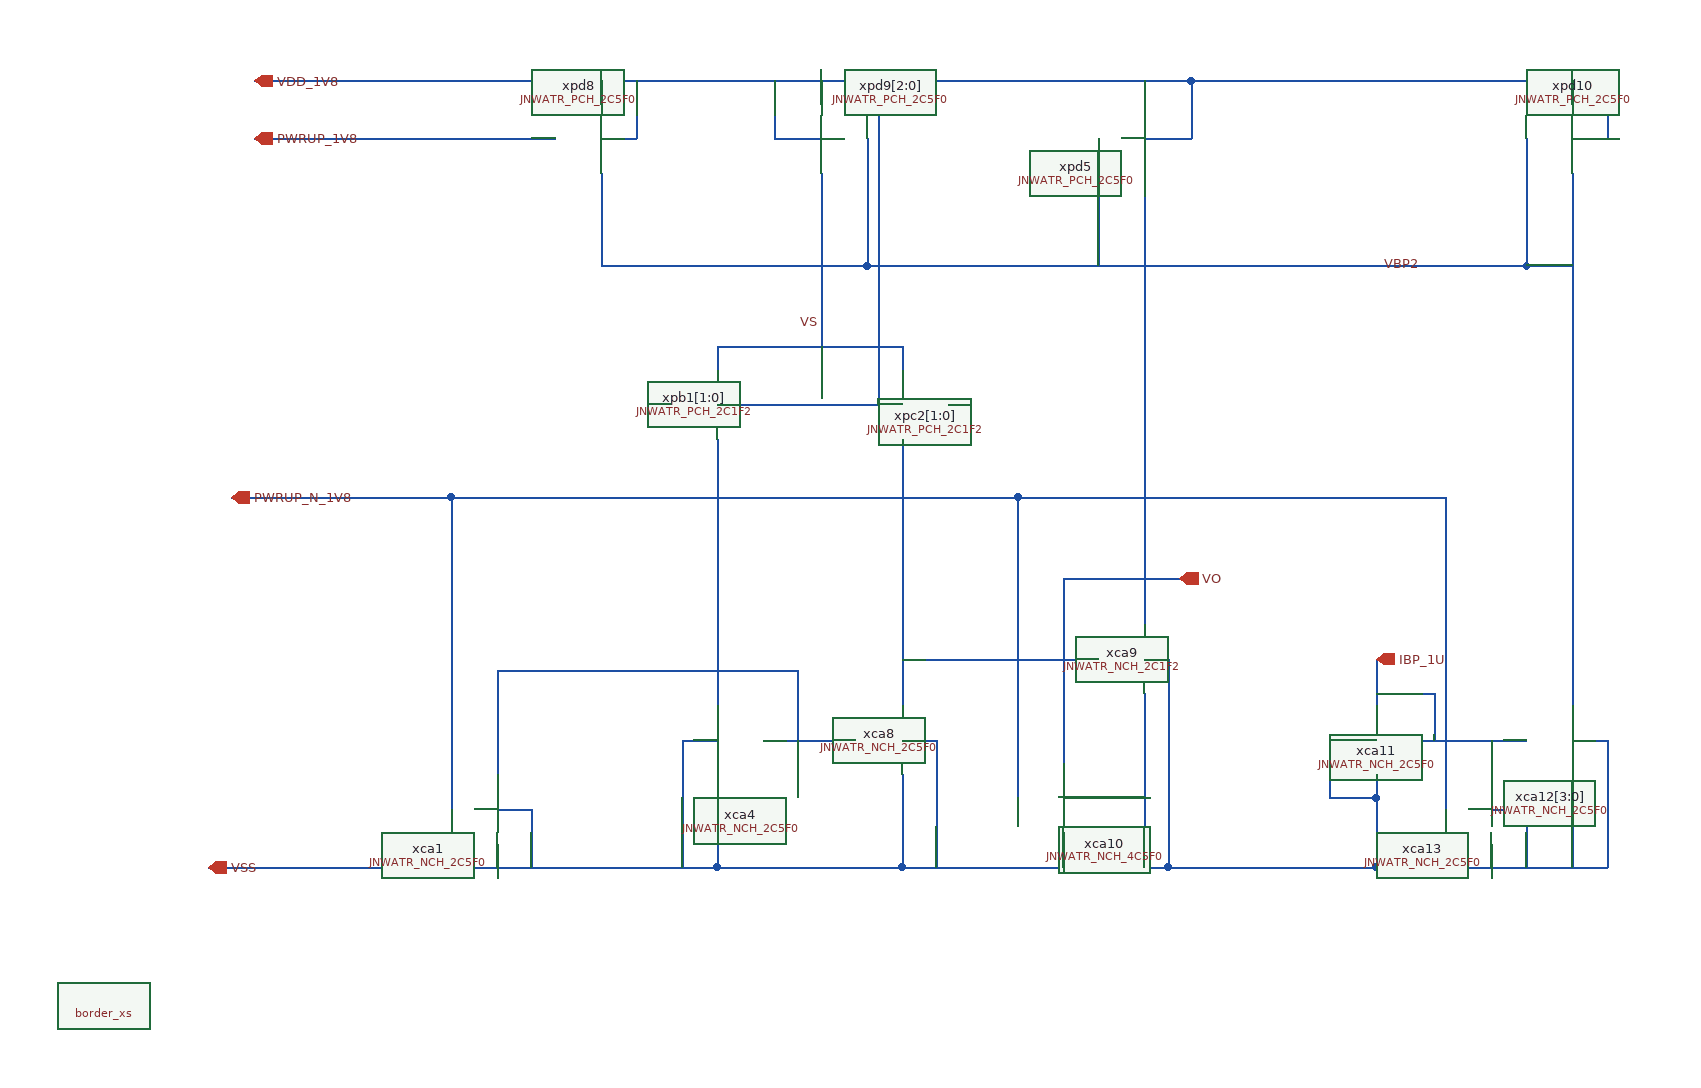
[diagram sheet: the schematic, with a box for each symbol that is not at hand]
v {xschem version=3.4.7 file_version=1.2}
G {}
K {}
V {}
S {}
E {}
N 90 -130 200 -130 {lab=VSS}
N 130 -810 190 -810 {lab=VDD_1V8}
N 190 -810 590 -810 {lab=VDD_1V8}
N 590 -810 630 -810 {lab=VDD_1V8}
N 530 -530 690 -530 {lab=VDD_1V8}
N 530 -580 530 -570 {lab=VS}
N 530 -580 600 -580 {lab=VS}
N 530 -570 530 -560 {lab=VS}
N 600 -580 690 -580 {lab=VS}
N 690 -580 690 -570 {lab=VS}
N 690 -570 690 -560 {lab=VS}
N 490 -130 530 -130 {lab=VSS}
N 530 -130 690 -130 {lab=VSS}
N 200 -130 490 -130 {lab=VSS}
N 670 -810 670 -530 {lab=VDD_1V8}
N 630 -810 670 -810 {lab=VDD_1V8}
N 860 -760 860 -710 {lab=VBP2}
N 900 -760 940 -760 {lab=VDD_1V8}
N 940 -810 940 -760 {lab=VDD_1V8}
N 670 -810 940 -810 {lab=VDD_1V8}
N 900 -810 900 -790 {lab=VDD_1V8}
N 690 -130 920 -130 {lab=VSS}
N 900 -380 930 -380 {lab=VO}
N 730 -530 750 -530 {lab=VIP}
N 470 -530 490 -530 {lab=VIN}
N 620 -590 620 -580 {lab=VS}
N 620 -600 620 -590 {lab=VS}
N 530 -210 530 -130 {lab=VSS}
N 690 -210 690 -130 {lab=VSS}
N 340 -180 370 -180 {lab=VSS}
N 370 -180 370 -130 {lab=VSS}
N 340 -150 340 -130 {lab=VSS}
N 340 -240 340 -210 {lab=#net1}
N 530 -500 530 -270 {lab=#net1}
N 690 -500 690 -270 {lab=#net2}
N 260 -760 320 -760 {lab=PWRUP_1V8}
N 130 -760 260 -760 {lab=PWRUP_1V8}
N 110 -450 290 -450 {lab=PWRUP_N_1V8}
N 290 -450 300 -450 {lab=PWRUP_N_1V8}
N 300 -450 300 -180 {lab=PWRUP_N_1V8}
N 300 -450 790 -450 {lab=PWRUP_N_1V8}
N 620 -730 620 -600 {lab=VS}
N 1100 -310 1100 -270 {lab=IBP_1U}
N 1060 -240 1100 -240 {lab=VSS}
N 1060 -240 1060 -190 {lab=VSS}
N 1060 -190 1100 -190 {lab=VSS}
N 1100 -210 1100 -190 {lab=VSS}
N 1100 -190 1100 -130 {lab=VSS}
N 920 -130 1100 -130 {lab=VSS}
N 1270 -240 1300 -240 {lab=VSS}
N 1300 -240 1300 -130 {lab=VSS}
N 1100 -130 1300 -130 {lab=VSS}
N 1270 -210 1270 -130 {lab=VSS}
N 1200 -180 1230 -180 {lab=VSS}
N 1230 -180 1230 -130 {lab=VSS}
N 1200 -150 1200 -130 {lab=VSS}
N 1140 -240 1230 -240 {lab=IBP_1U}
N 1200 -240 1200 -210 {lab=IBP_1U}
N 1270 -730 1270 -270 {lab=VBP2}
N 1270 -760 1300 -760 {lab=VDD_1V8}
N 1300 -810 1300 -760 {lab=VDD_1V8}
N 940 -810 1300 -810 {lab=VDD_1V8}
N 1270 -810 1270 -790 {lab=VDD_1V8}
N 580 -760 620 -760 {lab=VDD_1V8}
N 580 -810 580 -760 {lab=VDD_1V8}
N 620 -810 620 -790 {lab=VDD_1V8}
N 660 -760 660 -650 {lab=VBP2}
N 660 -650 1220 -650 {lab=VBP2}
N 1220 -650 1230 -650 {lab=VBP2}
N 1230 -760 1230 -650 {lab=VBP2}
N 790 -450 1160 -450 {lab=PWRUP_N_1V8}
N 1160 -450 1160 -180 {lab=PWRUP_N_1V8}
N 1230 -650 1270 -650 {lab=VBP2}
N 1100 -280 1150 -280 {lab=IBP_1U}
N 1150 -280 1150 -240 {lab=IBP_1U}
N 860 -710 860 -650 {lab=VBP2}
N 500 -240 530 -240 {lab=VSS}
N 500 -240 500 -130 {lab=VSS}
N 690 -240 720 -240 {lab=VSS}
N 720 -240 720 -130 {lab=VSS}
N 570 -240 650 -240 {lab=#net1}
N 530 -300 600 -300 {lab=#net1}
N 600 -300 600 -240 {lab=#net1}
N 340 -300 530 -300 {lab=#net1}
N 340 -300 340 -240 {lab=#net1}
N 690 -310 860 -310 {lab=#net2}
N 790 -450 790 -190 {lab=PWRUP_N_1V8}
N 830 -380 830 -220 {lab=VO}
N 830 -380 900 -380 {lab=VO}
N 900 -730 900 -340 {lab=VO}
N 900 -310 920 -310 {lab=VSS}
N 920 -310 920 -130 {lab=VSS}
N 900 -280 900 -130 {lab=VSS}
N 830 -190 900 -190 {lab=VSS}
N 830 -160 830 -130 {lab=VSS}
N 430 -760 460 -760 {lab=VDD_1V8}
N 460 -810 460 -760 {lab=VDD_1V8}
N 430 -810 430 -790 {lab=VDD_1V8}
N 430 -730 430 -650 {lab=VBP2}
N 430 -650 660 -650 {lab=VBP2}
N 320 -760 390 -760 {lab=PWRUP_1V8}
C {devices/opin.sym} 930 -380 0 0 {name=p1 lab=VO}
C {devices/ipin.sym} 750 -530 2 0 {name=p2 lab=VIP}
C {devices/ipin.sym} 470 -530 2 1 {name=p3 lab=VIN}
C {devices/ipin.sym} 130 -810 2 1 {name=p4 lab=VDD_1V8}
C {devices/ipin.sym} 90 -130 2 1 {name=p5 lab=VSS}
C {JNW_ATR_SKY130A/JNWATR_PCH_2C1F2.sym} 490 -530 0 0 {name=xpb1[1:0]}
C {JNW_ATR_SKY130A/JNWATR_PCH_2C1F2.sym} 730 -530 0 1 {name=xpc2[1:0]}
C {JNW_ATR_SKY130A/JNWATR_NCH_2C5F0.sym} 570 -240 0 1 {name=xca4}
C {JNW_ATR_SKY130A/JNWATR_NCH_2C5F0.sym} 650 -240 0 0 {name=xca8}
C {cborder/border_xs.sym} 0 -10 0 0 {user="Carsten Wulff" company="Carsten Wulff Software"}
C {JNW_ATR_SKY130A/JNWATR_PCH_2C5F0.sym} 860 -760 0 0 {name=xpd5}
C {JNW_ATR_SKY130A/JNWATR_NCH_2C1F2.sym} 860 -310 0 0 {name=xca9}
C {devices/ipin.sym} 110 -450 2 1 {name=p9 lab=PWRUP_N_1V8}
C {JNW_ATR_SKY130A/JNWATR_PCH_2C5F0.sym} 390 -760 0 0 {name=xpd8}
C {JNW_ATR_SKY130A/JNWATR_NCH_2C5F0.sym} 300 -180 0 0 {name=xca1}
C {devices/ipin.sym} 130 -760 2 1 {name=p10 lab=PWRUP_1V8}
C {devices/ipin.sym} 1100 -310 3 1 {name=p11 lab=IBP_1U}
C {JNW_ATR_SKY130A/JNWATR_NCH_4C5F0.sym} 790 -190 0 0 {name=xca10}
C {JNW_ATR_SKY130A/JNWATR_NCH_2C5F0.sym} 1140 -240 0 1 {name=xca11}
C {JNW_ATR_SKY130A/JNWATR_NCH_2C5F0.sym} 1230 -240 0 0 {name=xca12[3:0]
}
C {JNW_ATR_SKY130A/JNWATR_NCH_2C5F0.sym} 1160 -180 0 0 {name=xca13}
C {JNW_ATR_SKY130A/JNWATR_PCH_2C5F0.sym} 1230 -760 0 0 {name=xpd10}
C {JNW_ATR_SKY130A/JNWATR_PCH_2C5F0.sym} 660 -760 0 1 {name=xpd9[2:0]}
C {devices/lab_wire.sym} 620 -600 0 0 {name=p7 sig_type=std_logic lab=VS}
C {devices/lab_wire.sym} 1140 -650 0 0 {name=p13 sig_type=std_logic lab=VBP2}
